VERSION 5.7 ;
  NOWIREEXTENSIONATPIN ON ;
  DIVIDERCHAR "/" ;
  BUSBITCHARS "[]" ;
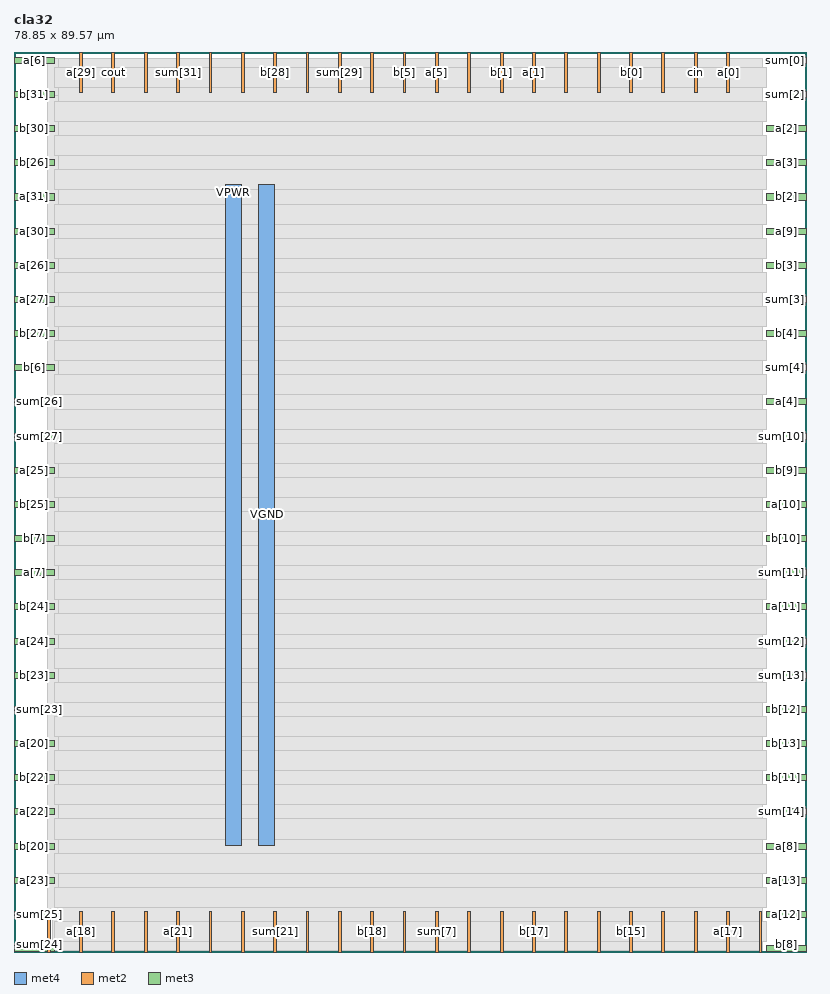
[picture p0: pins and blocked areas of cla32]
MACRO cla32
  CLASS BLOCK ;
  FOREIGN cla32 ;
  ORIGIN 0.000 0.000 ;
  SIZE 78.850 BY 89.570 ;
  PIN VGND
    DIRECTION INOUT ;
    USE GROUND ;
    PORT
      LAYER met4 ;
        RECT 24.340 10.640 25.940 76.400 ;
    END
  END VGND
  PIN VPWR
    DIRECTION INOUT ;
    USE POWER ;
    PORT
      LAYER met4 ;
        RECT 21.040 10.640 22.640 76.400 ;
    END
  END VPWR
  PIN a[0]
    DIRECTION INPUT ;
    USE SIGNAL ;
    ANTENNAGATEAREA 0.196500 ;
    PORT
      LAYER met2 ;
        RECT 70.930 85.570 71.210 89.570 ;
    END
  END a[0]
  PIN a[10]
    DIRECTION INPUT ;
    USE SIGNAL ;
    ANTENNAGATEAREA 0.196500 ;
    PORT
      LAYER met3 ;
        RECT 74.850 44.240 78.850 44.840 ;
    END
  END a[10]
  PIN a[11]
    DIRECTION INPUT ;
    USE SIGNAL ;
    ANTENNAGATEAREA 0.196500 ;
    PORT
      LAYER met3 ;
        RECT 74.850 34.040 78.850 34.640 ;
    END
  END a[11]
  PIN a[12]
    DIRECTION INPUT ;
    USE SIGNAL ;
    ANTENNAGATEAREA 0.196500 ;
    PORT
      LAYER met3 ;
        RECT 74.850 3.440 78.850 4.040 ;
    END
  END a[12]
  PIN a[13]
    DIRECTION INPUT ;
    USE SIGNAL ;
    ANTENNAGATEAREA 0.196500 ;
    PORT
      LAYER met3 ;
        RECT 74.850 6.840 78.850 7.440 ;
    END
  END a[13]
  PIN a[14]
    DIRECTION INPUT ;
    USE SIGNAL ;
    ANTENNAGATEAREA 0.196500 ;
    PORT
      LAYER met2 ;
        RECT 74.150 0.000 74.430 4.000 ;
    END
  END a[14]
  PIN a[15]
    DIRECTION INPUT ;
    USE SIGNAL ;
    ANTENNAGATEAREA 0.196500 ;
    PORT
      LAYER met2 ;
        RECT 58.050 0.000 58.330 4.000 ;
    END
  END a[15]
  PIN a[16]
    DIRECTION INPUT ;
    USE SIGNAL ;
    ANTENNAGATEAREA 0.196500 ;
    PORT
      LAYER met2 ;
        RECT 3.310 0.000 3.590 4.000 ;
    END
  END a[16]
  PIN a[17]
    DIRECTION INPUT ;
    USE SIGNAL ;
    ANTENNAGATEAREA 0.196500 ;
    PORT
      LAYER met2 ;
        RECT 70.930 0.000 71.210 4.000 ;
    END
  END a[17]
  PIN a[18]
    DIRECTION INPUT ;
    USE SIGNAL ;
    ANTENNAGATEAREA 0.196500 ;
    PORT
      LAYER met2 ;
        RECT 6.530 0.000 6.810 4.000 ;
    END
  END a[18]
  PIN a[19]
    DIRECTION INPUT ;
    USE SIGNAL ;
    ANTENNAGATEAREA 0.196500 ;
    PORT
      LAYER met2 ;
        RECT 9.750 0.000 10.030 4.000 ;
    END
  END a[19]
  PIN a[1]
    DIRECTION INPUT ;
    USE SIGNAL ;
    ANTENNAGATEAREA 0.196500 ;
    PORT
      LAYER met2 ;
        RECT 51.610 85.570 51.890 89.570 ;
    END
  END a[1]
  PIN a[20]
    DIRECTION INPUT ;
    USE SIGNAL ;
    ANTENNAGATEAREA 0.196500 ;
    PORT
      LAYER met3 ;
        RECT 0.000 20.440 4.000 21.040 ;
    END
  END a[20]
  PIN a[21]
    DIRECTION INPUT ;
    USE SIGNAL ;
    ANTENNAGATEAREA 0.196500 ;
    PORT
      LAYER met2 ;
        RECT 16.190 0.000 16.470 4.000 ;
    END
  END a[21]
  PIN a[22]
    DIRECTION INPUT ;
    USE SIGNAL ;
    ANTENNAGATEAREA 0.196500 ;
    PORT
      LAYER met3 ;
        RECT 0.000 13.640 4.000 14.240 ;
    END
  END a[22]
  PIN a[23]
    DIRECTION INPUT ;
    USE SIGNAL ;
    ANTENNAGATEAREA 0.196500 ;
    PORT
      LAYER met3 ;
        RECT 0.000 6.840 4.000 7.440 ;
    END
  END a[23]
  PIN a[24]
    DIRECTION INPUT ;
    USE SIGNAL ;
    ANTENNAGATEAREA 0.196500 ;
    PORT
      LAYER met3 ;
        RECT 0.000 30.640 4.000 31.240 ;
    END
  END a[24]
  PIN a[25]
    DIRECTION INPUT ;
    USE SIGNAL ;
    ANTENNAGATEAREA 0.196500 ;
    PORT
      LAYER met3 ;
        RECT 0.000 47.640 4.000 48.240 ;
    END
  END a[25]
  PIN a[26]
    DIRECTION INPUT ;
    USE SIGNAL ;
    ANTENNAGATEAREA 0.196500 ;
    PORT
      LAYER met3 ;
        RECT 0.000 68.040 4.000 68.640 ;
    END
  END a[26]
  PIN a[27]
    DIRECTION INPUT ;
    USE SIGNAL ;
    ANTENNAGATEAREA 0.196500 ;
    PORT
      LAYER met3 ;
        RECT 0.000 64.640 4.000 65.240 ;
    END
  END a[27]
  PIN a[28]
    DIRECTION INPUT ;
    USE SIGNAL ;
    ANTENNAGATEAREA 0.196500 ;
    PORT
      LAYER met2 ;
        RECT 29.070 85.570 29.350 89.570 ;
    END
  END a[28]
  PIN a[29]
    DIRECTION INPUT ;
    USE SIGNAL ;
    ANTENNAGATEAREA 0.196500 ;
    PORT
      LAYER met2 ;
        RECT 6.530 85.570 6.810 89.570 ;
    END
  END a[29]
  PIN a[2]
    DIRECTION INPUT ;
    USE SIGNAL ;
    ANTENNAGATEAREA 0.196500 ;
    PORT
      LAYER met3 ;
        RECT 74.850 81.640 78.850 82.240 ;
    END
  END a[2]
  PIN a[30]
    DIRECTION INPUT ;
    USE SIGNAL ;
    ANTENNAGATEAREA 0.196500 ;
    PORT
      LAYER met3 ;
        RECT 0.000 71.440 4.000 72.040 ;
    END
  END a[30]
  PIN a[31]
    DIRECTION INPUT ;
    USE SIGNAL ;
    ANTENNAGATEAREA 0.196500 ;
    PORT
      LAYER met3 ;
        RECT 0.000 74.840 4.000 75.440 ;
    END
  END a[31]
  PIN a[3]
    DIRECTION INPUT ;
    USE SIGNAL ;
    ANTENNAGATEAREA 0.196500 ;
    PORT
      LAYER met3 ;
        RECT 74.850 78.240 78.850 78.840 ;
    END
  END a[3]
  PIN a[4]
    DIRECTION INPUT ;
    USE SIGNAL ;
    ANTENNAGATEAREA 0.196500 ;
    PORT
      LAYER met3 ;
        RECT 74.850 54.440 78.850 55.040 ;
    END
  END a[4]
  PIN a[5]
    DIRECTION INPUT ;
    USE SIGNAL ;
    ANTENNAGATEAREA 0.196500 ;
    PORT
      LAYER met2 ;
        RECT 41.950 85.570 42.230 89.570 ;
    END
  END a[5]
  PIN a[6]
    DIRECTION INPUT ;
    USE SIGNAL ;
    ANTENNAGATEAREA 0.196500 ;
    PORT
      LAYER met3 ;
        RECT 0.000 88.440 4.000 89.040 ;
    END
  END a[6]
  PIN a[7]
    DIRECTION INPUT ;
    USE SIGNAL ;
    ANTENNAGATEAREA 0.196500 ;
    PORT
      LAYER met3 ;
        RECT 0.000 37.440 4.000 38.040 ;
    END
  END a[7]
  PIN a[8]
    DIRECTION INPUT ;
    USE SIGNAL ;
    ANTENNAGATEAREA 0.196500 ;
    PORT
      LAYER met3 ;
        RECT 74.850 10.240 78.850 10.840 ;
    END
  END a[8]
  PIN a[9]
    DIRECTION INPUT ;
    USE SIGNAL ;
    ANTENNAGATEAREA 0.196500 ;
    PORT
      LAYER met3 ;
        RECT 74.850 71.440 78.850 72.040 ;
    END
  END a[9]
  PIN b[0]
    DIRECTION INPUT ;
    USE SIGNAL ;
    ANTENNAGATEAREA 0.196500 ;
    PORT
      LAYER met2 ;
        RECT 61.270 85.570 61.550 89.570 ;
    END
  END b[0]
  PIN b[10]
    DIRECTION INPUT ;
    USE SIGNAL ;
    ANTENNAGATEAREA 0.196500 ;
    PORT
      LAYER met3 ;
        RECT 74.850 40.840 78.850 41.440 ;
    END
  END b[10]
  PIN b[11]
    DIRECTION INPUT ;
    USE SIGNAL ;
    ANTENNAGATEAREA 0.196500 ;
    PORT
      LAYER met3 ;
        RECT 74.850 17.040 78.850 17.640 ;
    END
  END b[11]
  PIN b[12]
    DIRECTION INPUT ;
    USE SIGNAL ;
    ANTENNAGATEAREA 0.196500 ;
    PORT
      LAYER met3 ;
        RECT 74.850 23.840 78.850 24.440 ;
    END
  END b[12]
  PIN b[13]
    DIRECTION INPUT ;
    USE SIGNAL ;
    ANTENNAGATEAREA 0.196500 ;
    PORT
      LAYER met3 ;
        RECT 74.850 20.440 78.850 21.040 ;
    END
  END b[13]
  PIN b[14]
    DIRECTION INPUT ;
    USE SIGNAL ;
    ANTENNAGATEAREA 0.196500 ;
    PORT
      LAYER met2 ;
        RECT 64.490 0.000 64.770 4.000 ;
    END
  END b[14]
  PIN b[15]
    DIRECTION INPUT ;
    USE SIGNAL ;
    ANTENNAGATEAREA 0.196500 ;
    PORT
      LAYER met2 ;
        RECT 61.270 0.000 61.550 4.000 ;
    END
  END b[15]
  PIN b[16]
    DIRECTION INPUT ;
    USE SIGNAL ;
    ANTENNAGATEAREA 0.196500 ;
    PORT
      LAYER met2 ;
        RECT 38.730 0.000 39.010 4.000 ;
    END
  END b[16]
  PIN b[17]
    DIRECTION INPUT ;
    USE SIGNAL ;
    ANTENNAGATEAREA 0.196500 ;
    PORT
      LAYER met2 ;
        RECT 51.610 0.000 51.890 4.000 ;
    END
  END b[17]
  PIN b[18]
    DIRECTION INPUT ;
    USE SIGNAL ;
    ANTENNAGATEAREA 0.196500 ;
    PORT
      LAYER met2 ;
        RECT 35.510 0.000 35.790 4.000 ;
    END
  END b[18]
  PIN b[19]
    DIRECTION INPUT ;
    USE SIGNAL ;
    ANTENNAGATEAREA 0.196500 ;
    PORT
      LAYER met2 ;
        RECT 29.070 0.000 29.350 4.000 ;
    END
  END b[19]
  PIN b[1]
    DIRECTION INPUT ;
    USE SIGNAL ;
    ANTENNAGATEAREA 0.196500 ;
    PORT
      LAYER met2 ;
        RECT 48.390 85.570 48.670 89.570 ;
    END
  END b[1]
  PIN b[20]
    DIRECTION INPUT ;
    USE SIGNAL ;
    ANTENNAGATEAREA 0.196500 ;
    PORT
      LAYER met3 ;
        RECT 0.000 10.240 4.000 10.840 ;
    END
  END b[20]
  PIN b[21]
    DIRECTION INPUT ;
    USE SIGNAL ;
    ANTENNAGATEAREA 0.196500 ;
    PORT
      LAYER met2 ;
        RECT 22.630 0.000 22.910 4.000 ;
    END
  END b[21]
  PIN b[22]
    DIRECTION INPUT ;
    USE SIGNAL ;
    ANTENNAGATEAREA 0.196500 ;
    PORT
      LAYER met3 ;
        RECT 0.000 17.040 4.000 17.640 ;
    END
  END b[22]
  PIN b[23]
    DIRECTION INPUT ;
    USE SIGNAL ;
    ANTENNAGATEAREA 0.196500 ;
    PORT
      LAYER met3 ;
        RECT 0.000 27.240 4.000 27.840 ;
    END
  END b[23]
  PIN b[24]
    DIRECTION INPUT ;
    USE SIGNAL ;
    ANTENNAGATEAREA 0.196500 ;
    PORT
      LAYER met3 ;
        RECT 0.000 34.040 4.000 34.640 ;
    END
  END b[24]
  PIN b[25]
    DIRECTION INPUT ;
    USE SIGNAL ;
    ANTENNAGATEAREA 0.196500 ;
    PORT
      LAYER met3 ;
        RECT 0.000 44.240 4.000 44.840 ;
    END
  END b[25]
  PIN b[26]
    DIRECTION INPUT ;
    USE SIGNAL ;
    ANTENNAGATEAREA 0.196500 ;
    PORT
      LAYER met3 ;
        RECT 0.000 78.240 4.000 78.840 ;
    END
  END b[26]
  PIN b[27]
    DIRECTION INPUT ;
    USE SIGNAL ;
    ANTENNAGATEAREA 0.196500 ;
    PORT
      LAYER met3 ;
        RECT 0.000 61.240 4.000 61.840 ;
    END
  END b[27]
  PIN b[28]
    DIRECTION INPUT ;
    USE SIGNAL ;
    ANTENNAGATEAREA 0.196500 ;
    PORT
      LAYER met2 ;
        RECT 25.850 85.570 26.130 89.570 ;
    END
  END b[28]
  PIN b[29]
    DIRECTION INPUT ;
    USE SIGNAL ;
    ANTENNAGATEAREA 0.196500 ;
    PORT
      LAYER met2 ;
        RECT 12.970 85.570 13.250 89.570 ;
    END
  END b[29]
  PIN b[2]
    DIRECTION INPUT ;
    USE SIGNAL ;
    ANTENNAGATEAREA 0.196500 ;
    PORT
      LAYER met3 ;
        RECT 74.850 74.840 78.850 75.440 ;
    END
  END b[2]
  PIN b[30]
    DIRECTION INPUT ;
    USE SIGNAL ;
    ANTENNAGATEAREA 0.196500 ;
    PORT
      LAYER met3 ;
        RECT 0.000 81.640 4.000 82.240 ;
    END
  END b[30]
  PIN b[31]
    DIRECTION INPUT ;
    USE SIGNAL ;
    ANTENNAGATEAREA 0.196500 ;
    PORT
      LAYER met3 ;
        RECT 0.000 85.040 4.000 85.640 ;
    END
  END b[31]
  PIN b[3]
    DIRECTION INPUT ;
    USE SIGNAL ;
    ANTENNAGATEAREA 0.196500 ;
    PORT
      LAYER met3 ;
        RECT 74.850 68.040 78.850 68.640 ;
    END
  END b[3]
  PIN b[4]
    DIRECTION INPUT ;
    USE SIGNAL ;
    ANTENNAGATEAREA 0.196500 ;
    PORT
      LAYER met3 ;
        RECT 74.850 61.240 78.850 61.840 ;
    END
  END b[4]
  PIN b[5]
    DIRECTION INPUT ;
    USE SIGNAL ;
    ANTENNAGATEAREA 0.196500 ;
    PORT
      LAYER met2 ;
        RECT 38.730 85.570 39.010 89.570 ;
    END
  END b[5]
  PIN b[6]
    DIRECTION INPUT ;
    USE SIGNAL ;
    ANTENNAGATEAREA 0.196500 ;
    PORT
      LAYER met3 ;
        RECT 0.000 57.840 4.000 58.440 ;
    END
  END b[6]
  PIN b[7]
    DIRECTION INPUT ;
    USE SIGNAL ;
    ANTENNAGATEAREA 0.196500 ;
    PORT
      LAYER met3 ;
        RECT 0.000 40.840 4.000 41.440 ;
    END
  END b[7]
  PIN b[8]
    DIRECTION INPUT ;
    USE SIGNAL ;
    ANTENNAGATEAREA 0.196500 ;
    PORT
      LAYER met3 ;
        RECT 74.850 0.040 78.850 0.640 ;
    END
  END b[8]
  PIN b[9]
    DIRECTION INPUT ;
    USE SIGNAL ;
    ANTENNAGATEAREA 0.196500 ;
    PORT
      LAYER met3 ;
        RECT 74.850 47.640 78.850 48.240 ;
    END
  END b[9]
  PIN cin
    DIRECTION INPUT ;
    USE SIGNAL ;
    ANTENNAGATEAREA 0.196500 ;
    PORT
      LAYER met2 ;
        RECT 67.710 85.570 67.990 89.570 ;
    END
  END cin
  PIN cout
    DIRECTION OUTPUT ;
    USE SIGNAL ;
    ANTENNADIFFAREA 0.445500 ;
    PORT
      LAYER met2 ;
        RECT 9.750 85.570 10.030 89.570 ;
    END
  END cout
  PIN sum[0]
    DIRECTION OUTPUT ;
    USE SIGNAL ;
    ANTENNADIFFAREA 0.445500 ;
    PORT
      LAYER met3 ;
        RECT 74.850 88.440 78.850 89.040 ;
    END
  END sum[0]
  PIN sum[10]
    DIRECTION OUTPUT ;
    USE SIGNAL ;
    ANTENNADIFFAREA 0.445500 ;
    PORT
      LAYER met3 ;
        RECT 74.850 51.040 78.850 51.640 ;
    END
  END sum[10]
  PIN sum[11]
    DIRECTION OUTPUT ;
    USE SIGNAL ;
    ANTENNADIFFAREA 0.445500 ;
    PORT
      LAYER met3 ;
        RECT 74.850 37.440 78.850 38.040 ;
    END
  END sum[11]
  PIN sum[12]
    DIRECTION OUTPUT ;
    USE SIGNAL ;
    ANTENNADIFFAREA 0.445500 ;
    PORT
      LAYER met3 ;
        RECT 74.850 30.640 78.850 31.240 ;
    END
  END sum[12]
  PIN sum[13]
    DIRECTION OUTPUT ;
    USE SIGNAL ;
    ANTENNADIFFAREA 0.445500 ;
    PORT
      LAYER met3 ;
        RECT 74.850 27.240 78.850 27.840 ;
    END
  END sum[13]
  PIN sum[14]
    DIRECTION OUTPUT ;
    USE SIGNAL ;
    ANTENNADIFFAREA 0.445500 ;
    PORT
      LAYER met3 ;
        RECT 74.850 13.640 78.850 14.240 ;
    END
  END sum[14]
  PIN sum[15]
    DIRECTION OUTPUT ;
    USE SIGNAL ;
    ANTENNADIFFAREA 0.445500 ;
    PORT
      LAYER met2 ;
        RECT 67.710 0.000 67.990 4.000 ;
    END
  END sum[15]
  PIN sum[16]
    DIRECTION OUTPUT ;
    USE SIGNAL ;
    ANTENNADIFFAREA 0.445500 ;
    PORT
      LAYER met2 ;
        RECT 45.170 0.000 45.450 4.000 ;
    END
  END sum[16]
  PIN sum[17]
    DIRECTION OUTPUT ;
    USE SIGNAL ;
    ANTENNADIFFAREA 0.445500 ;
    PORT
      LAYER met2 ;
        RECT 54.830 0.000 55.110 4.000 ;
    END
  END sum[17]
  PIN sum[18]
    DIRECTION OUTPUT ;
    USE SIGNAL ;
    ANTENNADIFFAREA 0.445500 ;
    PORT
      LAYER met2 ;
        RECT 48.390 0.000 48.670 4.000 ;
    END
  END sum[18]
  PIN sum[19]
    DIRECTION OUTPUT ;
    USE SIGNAL ;
    ANTENNADIFFAREA 0.445500 ;
    PORT
      LAYER met2 ;
        RECT 12.970 0.000 13.250 4.000 ;
    END
  END sum[19]
  PIN sum[1]
    DIRECTION OUTPUT ;
    USE SIGNAL ;
    ANTENNADIFFAREA 0.445500 ;
    PORT
      LAYER met2 ;
        RECT 58.050 85.570 58.330 89.570 ;
    END
  END sum[1]
  PIN sum[20]
    DIRECTION OUTPUT ;
    USE SIGNAL ;
    ANTENNADIFFAREA 0.445500 ;
    PORT
      LAYER met2 ;
        RECT 32.290 0.000 32.570 4.000 ;
    END
  END sum[20]
  PIN sum[21]
    DIRECTION OUTPUT ;
    USE SIGNAL ;
    ANTENNADIFFAREA 0.445500 ;
    PORT
      LAYER met2 ;
        RECT 25.850 0.000 26.130 4.000 ;
    END
  END sum[21]
  PIN sum[22]
    DIRECTION OUTPUT ;
    USE SIGNAL ;
    ANTENNADIFFAREA 0.445500 ;
    PORT
      LAYER met2 ;
        RECT 19.410 0.000 19.690 4.000 ;
    END
  END sum[22]
  PIN sum[23]
    DIRECTION OUTPUT ;
    USE SIGNAL ;
    ANTENNADIFFAREA 0.445500 ;
    PORT
      LAYER met3 ;
        RECT 0.000 23.840 4.000 24.440 ;
    END
  END sum[23]
  PIN sum[24]
    DIRECTION OUTPUT ;
    USE SIGNAL ;
    ANTENNADIFFAREA 0.445500 ;
    PORT
      LAYER met3 ;
        RECT 0.000 0.040 4.000 0.640 ;
    END
  END sum[24]
  PIN sum[25]
    DIRECTION OUTPUT ;
    USE SIGNAL ;
    ANTENNADIFFAREA 0.445500 ;
    PORT
      LAYER met3 ;
        RECT 0.000 3.440 4.000 4.040 ;
    END
  END sum[25]
  PIN sum[26]
    DIRECTION OUTPUT ;
    USE SIGNAL ;
    ANTENNADIFFAREA 0.445500 ;
    PORT
      LAYER met3 ;
        RECT 0.000 54.440 4.000 55.040 ;
    END
  END sum[26]
  PIN sum[27]
    DIRECTION OUTPUT ;
    USE SIGNAL ;
    ANTENNADIFFAREA 0.445500 ;
    PORT
      LAYER met3 ;
        RECT 0.000 51.040 4.000 51.640 ;
    END
  END sum[27]
  PIN sum[28]
    DIRECTION OUTPUT ;
    USE SIGNAL ;
    ANTENNADIFFAREA 0.445500 ;
    PORT
      LAYER met2 ;
        RECT 19.410 85.570 19.690 89.570 ;
    END
  END sum[28]
  PIN sum[29]
    DIRECTION OUTPUT ;
    USE SIGNAL ;
    ANTENNADIFFAREA 0.445500 ;
    PORT
      LAYER met2 ;
        RECT 32.290 85.570 32.570 89.570 ;
    END
  END sum[29]
  PIN sum[2]
    DIRECTION OUTPUT ;
    USE SIGNAL ;
    ANTENNADIFFAREA 0.445500 ;
    PORT
      LAYER met3 ;
        RECT 74.850 85.040 78.850 85.640 ;
    END
  END sum[2]
  PIN sum[30]
    DIRECTION OUTPUT ;
    USE SIGNAL ;
    ANTENNADIFFAREA 0.445500 ;
    PORT
      LAYER met2 ;
        RECT 22.630 85.570 22.910 89.570 ;
    END
  END sum[30]
  PIN sum[31]
    DIRECTION OUTPUT ;
    USE SIGNAL ;
    ANTENNADIFFAREA 0.445500 ;
    PORT
      LAYER met2 ;
        RECT 16.190 85.570 16.470 89.570 ;
    END
  END sum[31]
  PIN sum[3]
    DIRECTION OUTPUT ;
    USE SIGNAL ;
    ANTENNADIFFAREA 0.445500 ;
    PORT
      LAYER met3 ;
        RECT 74.850 64.640 78.850 65.240 ;
    END
  END sum[3]
  PIN sum[4]
    DIRECTION OUTPUT ;
    USE SIGNAL ;
    ANTENNADIFFAREA 0.445500 ;
    PORT
      LAYER met3 ;
        RECT 74.850 57.840 78.850 58.440 ;
    END
  END sum[4]
  PIN sum[5]
    DIRECTION OUTPUT ;
    USE SIGNAL ;
    ANTENNADIFFAREA 0.445500 ;
    PORT
      LAYER met2 ;
        RECT 45.170 85.570 45.450 89.570 ;
    END
  END sum[5]
  PIN sum[6]
    DIRECTION OUTPUT ;
    USE SIGNAL ;
    ANTENNADIFFAREA 0.445500 ;
    PORT
      LAYER met2 ;
        RECT 35.510 85.570 35.790 89.570 ;
    END
  END sum[6]
  PIN sum[7]
    DIRECTION OUTPUT ;
    USE SIGNAL ;
    ANTENNADIFFAREA 0.445500 ;
    PORT
      LAYER met2 ;
        RECT 41.950 0.000 42.230 4.000 ;
    END
  END sum[7]
  PIN sum[8]
    DIRECTION OUTPUT ;
    USE SIGNAL ;
    ANTENNADIFFAREA 0.445500 ;
    PORT
      LAYER met2 ;
        RECT 54.830 85.570 55.110 89.570 ;
    END
  END sum[8]
  PIN sum[9]
    DIRECTION OUTPUT ;
    USE SIGNAL ;
    ANTENNADIFFAREA 0.445500 ;
    PORT
      LAYER met2 ;
        RECT 64.490 85.570 64.770 89.570 ;
    END
  END sum[9]
  OBS
      LAYER nwell ;
        RECT 5.330 10.795 73.330 76.245 ;
      LAYER li1 ;
        RECT 5.520 10.795 73.140 76.245 ;
      LAYER met1 ;
        RECT 3.290 6.500 74.450 76.400 ;
      LAYER met2 ;
        RECT 3.320 85.290 6.250 88.925 ;
        RECT 7.090 85.290 9.470 88.925 ;
        RECT 10.310 85.290 12.690 88.925 ;
        RECT 13.530 85.290 15.910 88.925 ;
        RECT 16.750 85.290 19.130 88.925 ;
        RECT 19.970 85.290 22.350 88.925 ;
        RECT 23.190 85.290 25.570 88.925 ;
        RECT 26.410 85.290 28.790 88.925 ;
        RECT 29.630 85.290 32.010 88.925 ;
        RECT 32.850 85.290 35.230 88.925 ;
        RECT 36.070 85.290 38.450 88.925 ;
        RECT 39.290 85.290 41.670 88.925 ;
        RECT 42.510 85.290 44.890 88.925 ;
        RECT 45.730 85.290 48.110 88.925 ;
        RECT 48.950 85.290 51.330 88.925 ;
        RECT 52.170 85.290 54.550 88.925 ;
        RECT 55.390 85.290 57.770 88.925 ;
        RECT 58.610 85.290 60.990 88.925 ;
        RECT 61.830 85.290 64.210 88.925 ;
        RECT 65.050 85.290 67.430 88.925 ;
        RECT 68.270 85.290 70.650 88.925 ;
        RECT 71.490 85.290 74.420 88.925 ;
        RECT 3.320 4.280 74.420 85.290 ;
        RECT 3.870 0.155 6.250 4.280 ;
        RECT 7.090 0.155 9.470 4.280 ;
        RECT 10.310 0.155 12.690 4.280 ;
        RECT 13.530 0.155 15.910 4.280 ;
        RECT 16.750 0.155 19.130 4.280 ;
        RECT 19.970 0.155 22.350 4.280 ;
        RECT 23.190 0.155 25.570 4.280 ;
        RECT 26.410 0.155 28.790 4.280 ;
        RECT 29.630 0.155 32.010 4.280 ;
        RECT 32.850 0.155 35.230 4.280 ;
        RECT 36.070 0.155 38.450 4.280 ;
        RECT 39.290 0.155 41.670 4.280 ;
        RECT 42.510 0.155 44.890 4.280 ;
        RECT 45.730 0.155 48.110 4.280 ;
        RECT 48.950 0.155 51.330 4.280 ;
        RECT 52.170 0.155 54.550 4.280 ;
        RECT 55.390 0.155 57.770 4.280 ;
        RECT 58.610 0.155 60.990 4.280 ;
        RECT 61.830 0.155 64.210 4.280 ;
        RECT 65.050 0.155 67.430 4.280 ;
        RECT 68.270 0.155 70.650 4.280 ;
        RECT 71.490 0.155 73.870 4.280 ;
      LAYER met3 ;
        RECT 4.400 88.040 74.450 88.905 ;
        RECT 3.990 86.040 74.850 88.040 ;
        RECT 4.400 84.640 74.450 86.040 ;
        RECT 3.990 82.640 74.850 84.640 ;
        RECT 4.400 81.240 74.450 82.640 ;
        RECT 3.990 79.240 74.850 81.240 ;
        RECT 4.400 77.840 74.450 79.240 ;
        RECT 3.990 75.840 74.850 77.840 ;
        RECT 4.400 74.440 74.450 75.840 ;
        RECT 3.990 72.440 74.850 74.440 ;
        RECT 4.400 71.040 74.450 72.440 ;
        RECT 3.990 69.040 74.850 71.040 ;
        RECT 4.400 67.640 74.450 69.040 ;
        RECT 3.990 65.640 74.850 67.640 ;
        RECT 4.400 64.240 74.450 65.640 ;
        RECT 3.990 62.240 74.850 64.240 ;
        RECT 4.400 60.840 74.450 62.240 ;
        RECT 3.990 58.840 74.850 60.840 ;
        RECT 4.400 57.440 74.450 58.840 ;
        RECT 3.990 55.440 74.850 57.440 ;
        RECT 4.400 54.040 74.450 55.440 ;
        RECT 3.990 52.040 74.850 54.040 ;
        RECT 4.400 50.640 74.450 52.040 ;
        RECT 3.990 48.640 74.850 50.640 ;
        RECT 4.400 47.240 74.450 48.640 ;
        RECT 3.990 45.240 74.850 47.240 ;
        RECT 4.400 43.840 74.450 45.240 ;
        RECT 3.990 41.840 74.850 43.840 ;
        RECT 4.400 40.440 74.450 41.840 ;
        RECT 3.990 38.440 74.850 40.440 ;
        RECT 4.400 37.040 74.450 38.440 ;
        RECT 3.990 35.040 74.850 37.040 ;
        RECT 4.400 33.640 74.450 35.040 ;
        RECT 3.990 31.640 74.850 33.640 ;
        RECT 4.400 30.240 74.450 31.640 ;
        RECT 3.990 28.240 74.850 30.240 ;
        RECT 4.400 26.840 74.450 28.240 ;
        RECT 3.990 24.840 74.850 26.840 ;
        RECT 4.400 23.440 74.450 24.840 ;
        RECT 3.990 21.440 74.850 23.440 ;
        RECT 4.400 20.040 74.450 21.440 ;
        RECT 3.990 18.040 74.850 20.040 ;
        RECT 4.400 16.640 74.450 18.040 ;
        RECT 3.990 14.640 74.850 16.640 ;
        RECT 4.400 13.240 74.450 14.640 ;
        RECT 3.990 11.240 74.850 13.240 ;
        RECT 4.400 9.840 74.450 11.240 ;
        RECT 3.990 7.840 74.850 9.840 ;
        RECT 4.400 6.440 74.450 7.840 ;
        RECT 3.990 4.440 74.850 6.440 ;
        RECT 4.400 3.040 74.450 4.440 ;
        RECT 3.990 1.040 74.850 3.040 ;
        RECT 4.400 0.175 74.450 1.040 ;
  END
END cla32
END LIBRARY

